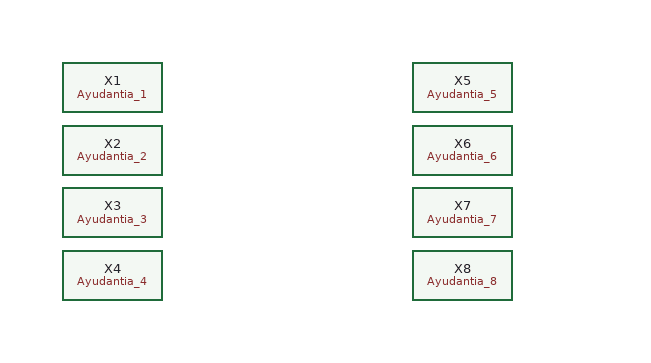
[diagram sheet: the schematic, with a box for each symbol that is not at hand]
v {xschem version=3.4.5 file_version=1.2
}
G {}
K {}
V {}
S {}
E {}
C {title.sym} -4260 -220 0 0 {name=l1 author="Prof: Jorge Marín , Ayudante: Andrés Martínez"}
C {../Ayudantias/Ayudantia_1/Ayudantia_1.sym} -3970 -370 0 0 {name=X1}
C {../Ayudantias/Ayudantia_2/Ayudantia_2.sym} -3970 -320 0 0 {name=X2}
C {../Ayudantias/Ayudantia_3/Ayudantia_3.sym} -3970 -270 0 0 {name=X3}
C {../Ayudantias/Ayudantia_4/Ayudantia_4.sym} -3970 -220 0 0 {name=X4}
C {../Ayudantias/Ayudantia_5/Ayudantia_5.sym} -3690 -370 0 0 {name=X5}
C {../Ayudantias/Ayudantia_6/Ayudantia_6.sym} -3690 -320 0 0 {name=X6}
C {../Ayudantias/Ayudantia_7/Ayudantia_7.sym} -3690 -270 0 0 {name=X7}
C {../Ayudantias/Ayudantia_8/Ayudantia_8.sym} -3690 -220 0 0 {name=X8}
